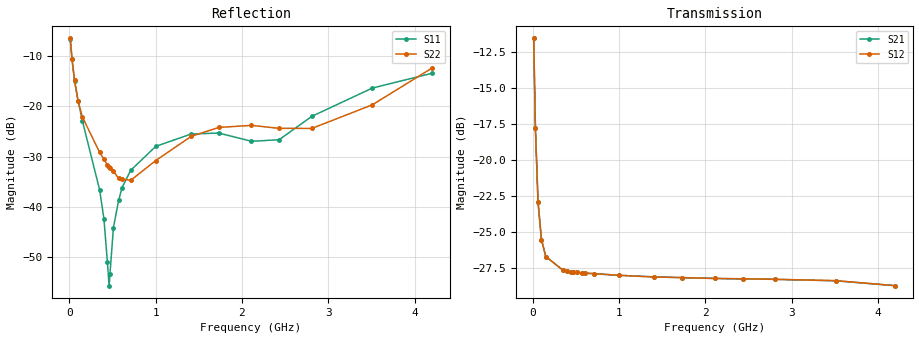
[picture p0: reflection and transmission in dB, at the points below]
! Integrated Device Technology
! Corporate Headquarters
! 6024 Silver Creek Valley Road
! San Jose, CA 95138  USA
! Phone:  1-408-284-8200
! Toll Free:  1-800-223-1366
! Webpage:  http://www.idt.com/
! Timing and RF Division
! 515 Groton Road, Suite 102
! Westford, MA 01886-6024
! Device:  F1950
! Description: 7-bit 0.25 dB Digital Step Attenuator
! Frequency:  150.0 -  4000.00 MHz
! Package:  4x4 mm Thin QFN Plastic Package: 24 pin
! Ports:  2 RF, 12 DC
!  Pin  1  = D0
!  Pin  2  = VDD
!  Pin  3  = Vmode
!  Pin  4  = GND
!  Pin  5  = RF1  =  Port 1
!  Pin  6  = GND
!  Pin  7  = GND
!  Pin  8  = GND
!  Pin  9  = GND
!  Pin 10  = GND
!  Pin 11  = GND
!  Pin 12  = GND
!  Pin 13  = GND
!  Pin 14  = RF2  =  Port 2
!  Pin 15  = GND
!  Pin 16  = LE
!  Pin 17  = CLK
!  Pin 18  = DATE
!  Pin 19  = D6
!  Pin 20  = D5
!  Pin 21  = D4
!  Pin 22  = D3
!  Pin 23  = D2
!  Pin 24  = D1
! State:  108
! Atten State:  27.00 dB
! Voltage:  +5.00 Volts
! Current:  Not Measured mA
! Data:  The device was measured on a the F195X evaluation board which has
!  individual transmission lines to the RF pins.  Data was collected
!  using a calibrated network analyzer.  The evaluation board was
!  de-embedded using a TRL calibration technique.
!  The reference plane is the edge of the package pin.
! Misc:  Board 2019
!  Action Tracker AT0250
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# GHz S dB R 50
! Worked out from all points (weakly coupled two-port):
!   420 points, 10 MHz to 4.2 GHz, reference 50 ohm
!   highest |S21| = -11.56 dB at 10 MHz (marker M1); lowest = -28.7 dB at 4.2 GHz (marker M2)
!   lowest |S11| = -55.6 dB at 460 MHz (marker M3), VSWR 1.00, Z = 49.8 - j0.0551 ohm
!   |S11| at or under -10 dB: 26.34 MHz to end of sweep
!   |S22| runs from -35.0 to -6.5 dB; largest |S21 - S12| = 9.8e-05
!   S11 on the Smith chart (normalised r, x): 10 MHz: 1.99, -1.10; 30 MHz: 1.29, -0.63; 60 MHz: 1.11, -0.36; 440 MHz: 1.00, -0.01; 4.2 GHz: 0.69, +0.17
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0.01  -6.66 -27.9  -11.56 -37.8  -11.56 -37.8  -6.54 -28.9
0.03  -10.68 -50.1  -17.78 -55.6  -17.78 -55.6  -10.60 -51.8
0.06  -15.05 -63.3  -22.87 -50.4  -22.87 -50.4  -14.83 -64.9
0.1  -18.91 -70.2  -25.51 -38.5  -25.51 -38.5  -18.89 -70.6
0.15  -22.87 -72.2  -26.68 -29.0  -26.68 -29.0  -22.14 -74.9
0.35  -36.58 -70.2  -27.63 -16.6  -27.63 -16.6  -29.16 -85.8
0.4  -42.39 -74.8  -27.69 -15.6  -27.68 -15.6  -30.53 -87.9
0.44  -50.84 -98.8  -27.72 -15.1  -27.73 -15.1  -31.64 -92.6
0.46  -55.63 -160.5  -27.74 -14.9  -27.74 -14.9  -32.04 -96.0
0.47  -53.30 165.4  -27.75 -14.8  -27.75 -14.8  -32.19 -97.6
0.51  -44.12 140.6  -27.77 -14.5  -27.78 -14.5  -32.87 -101.7
0.57  -38.70 135.0  -27.81 -14.2  -27.81 -14.3  -34.35 -112.4
0.61  -36.16 136.5  -27.83 -14.2  -27.83 -14.2  -34.49 -120.7
0.71  -32.74 137.8  -27.87 -14.2  -27.87 -14.3  -34.72 -140.3
1  -27.98 147.6  -27.98 -15.5  -27.98 -15.5  -30.80 179.0
1.41  -25.53 162.6  -28.09 -18.1  -28.10 -18.1  -26.00 160.6
1.73  -25.33 167.8  -28.14 -20.4  -28.14 -20.4  -24.22 152.2
2.11  -26.97 157.3  -28.20 -23.9  -28.20 -23.9  -23.81 142.3
2.43  -26.66 125.8  -28.23 -26.3  -28.22 -26.3  -24.40 131.6
2.81  -22.01 105.1  -28.26 -29.9  -28.26 -30.0  -24.41 116.3
3.51  -16.41 117.2  -28.36 -36.1  -28.35 -36.1  -19.73 113.4
4.2  -13.48 145.3  -28.70 -39.8  -28.70 -39.9  -12.46 127.2
